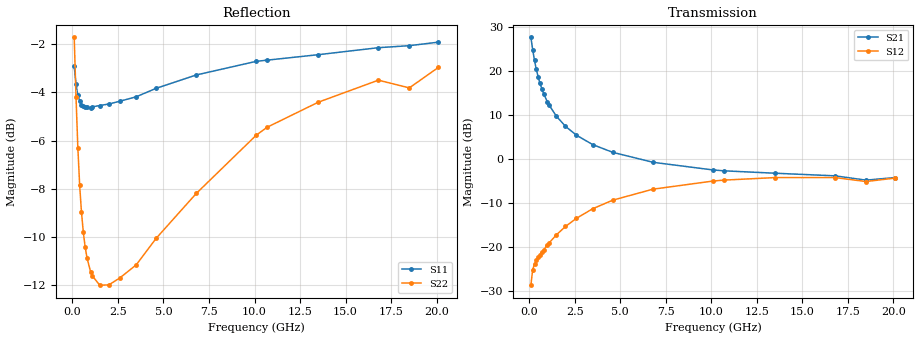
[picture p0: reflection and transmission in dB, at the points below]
!  Infineon Technologies AG
! BFR380L3 , PF131585-7, No.6, Th 09.10.01, soldered on pcb-board, measured with PP GSG850
!  Vce=0.5 V,  Ic=10.0 mA
! Common Emitter S-Parameters:  15. November 2001
#  GHz  S  MA  R  50
! f  S11  S21  S12  S22
! GHz  Mag  Ang  Mag  Ang  Mag  Ang  Mag  Ang
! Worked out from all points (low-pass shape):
!   201 points, 100 MHz to 20.1 GHz, reference 50 ohm
!   highest |S21| = 27.74 dB at 100 MHz (marker M1); lowest = -4.8 dB at 18.5 GHz (marker M2)
!   |S21| within 3 dB of the highest: start of sweep to 208.9 MHz
!   lowest |S11| = -4.6 dB at 1 GHz (marker M3), VSWR 3.84, Z = 13.1 - j2.66 ohm
!   |S11| at or under -10 dB: nowhere
!   |S22| runs from -12.1 to -1.7 dB; largest |S21 - S12| = 24
!   S11 on the Smith chart (normalised r, x): 100 MHz: 0.61, -1.55; 300 MHz: 0.30, -0.52; 1.1 GHz: 0.26, -0.03; 4.6 GHz: 0.27, +0.50; 10.7 GHz: 0.41, +1.27; 20.1 GHz: 0.92, +2.58
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0.1  0.7152 -60.3  24.39 145.5  0.03646 61.5  0.8217 -41.7
0.2  0.6563 -98.8  17.71 124.5  0.05488 49.8  0.6169 -69.1
0.3  0.6226 -121.9  13.31 112.8  0.06363 44.9  0.4841 -86.8
0.4  0.6057 -136.7  10.51 105.2  0.06988 43.3  0.4044 -99.8
0.5  0.5952 -147.2  8.623 99.6  0.07532 43.8  0.3552 -110.0
0.6  0.5906 -154.7  7.297 95.4  0.08113 44.9  0.3231 -118.1
0.7  0.5889 -160.8  6.329 91.8  0.08637 45.9  0.3013 -125.1
0.8  0.5882 -165.6  5.577 88.7  0.09223 47.4  0.2858 -130.8
1  0.5866 -173.5  4.517 83.6  0.1041 49.4  0.2671 -140.2
1.1  0.5892 -176.7  4.131 81.3  0.1104 50.3  0.2618 -144.0
1.5  0.5926 172.7  3.08 73.1  0.1364 52.6  0.2506 -155.7
2  0.5971 162.2  2.361 64.4  0.17 53.1  0.2508 -165.7
2.6  0.605 151.9  1.87 55.1  0.2107 51.9  0.2593 -174.8
3.5  0.618 138.3  1.458 42.8  0.2713 47.9  0.276 174.7
4.6  0.6437 124.2  1.191 30.4  0.3396 41.7  0.3136 162.9
6.8  0.6862 101.0  0.9179 10.6  0.4528 27.1  0.3888 141.3
10.1  0.7326 76.3  0.7505 -8.6  0.5607 6.5  0.5144 114.9
10.7  0.7368 72.7  0.7335 -11.4  0.5746 2.8  0.5343 110.0
13.5  0.7563 59.4  0.6888 -23.3  0.6141 -13.0  0.6022 90.9
16.8  0.7821 47.6  0.643 -34.5  0.6141 -27.7  0.6693 72.4
18.5  0.7897 45.3  0.5744 -41.7  0.5537 -35.8  0.645 67.7
20.1  0.8032 38.4  0.6145 -45.1  0.6061 -40.4  0.7117 57.7
